VERSION 5.7 ;
  NOWIREEXTENSIONATPIN ON ;
  DIVIDERCHAR "/" ;
  BUSBITCHARS "[]" ;
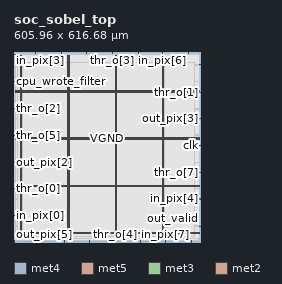
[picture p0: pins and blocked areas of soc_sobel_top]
MACRO soc_sobel_top
  CLASS BLOCK ;
  FOREIGN soc_sobel_top ;
  ORIGIN 0.000 0.000 ;
  SIZE 605.960 BY 616.680 ;
  PIN VGND
    DIRECTION INOUT ;
    USE GROUND ;
    PORT
      LAYER met4 ;
        RECT 24.340 10.640 25.940 604.080 ;
    END
    PORT
      LAYER met4 ;
        RECT 177.940 10.640 179.540 604.080 ;
    END
    PORT
      LAYER met4 ;
        RECT 331.540 10.640 333.140 604.080 ;
    END
    PORT
      LAYER met4 ;
        RECT 485.140 10.640 486.740 604.080 ;
    END
    PORT
      LAYER met5 ;
        RECT 5.280 30.030 600.540 31.630 ;
    END
    PORT
      LAYER met5 ;
        RECT 5.280 183.210 600.540 184.810 ;
    END
    PORT
      LAYER met5 ;
        RECT 5.280 336.390 600.540 337.990 ;
    END
    PORT
      LAYER met5 ;
        RECT 5.280 489.570 600.540 491.170 ;
    END
  END VGND
  PIN VPWR
    DIRECTION INOUT ;
    USE POWER ;
    PORT
      LAYER met4 ;
        RECT 21.040 10.640 22.640 604.080 ;
    END
    PORT
      LAYER met4 ;
        RECT 174.640 10.640 176.240 604.080 ;
    END
    PORT
      LAYER met4 ;
        RECT 328.240 10.640 329.840 604.080 ;
    END
    PORT
      LAYER met4 ;
        RECT 481.840 10.640 483.440 604.080 ;
    END
    PORT
      LAYER met5 ;
        RECT 5.280 26.730 600.540 28.330 ;
    END
    PORT
      LAYER met5 ;
        RECT 5.280 179.910 600.540 181.510 ;
    END
    PORT
      LAYER met5 ;
        RECT 5.280 333.090 600.540 334.690 ;
    END
    PORT
      LAYER met5 ;
        RECT 5.280 486.270 600.540 487.870 ;
    END
  END VPWR
  PIN clk
    DIRECTION INPUT ;
    USE SIGNAL ;
    ANTENNAGATEAREA 0.852000 ;
    PORT
      LAYER met3 ;
        RECT 601.960 312.840 605.960 313.440 ;
    END
  END clk
  PIN cpu_wrote_filter
    DIRECTION OUTPUT TRISTATE ;
    USE SIGNAL ;
    ANTENNADIFFAREA 0.795200 ;
    PORT
      LAYER met3 ;
        RECT 0.000 520.240 4.000 520.840 ;
    END
  END cpu_wrote_filter
  PIN in_pix[0]
    DIRECTION INPUT ;
    USE SIGNAL ;
    ANTENNAGATEAREA 0.247500 ;
    PORT
      LAYER met3 ;
        RECT 0.000 85.040 4.000 85.640 ;
    END
  END in_pix[0]
  PIN in_pix[1]
    DIRECTION INPUT ;
    USE SIGNAL ;
    ANTENNAGATEAREA 0.159000 ;
    PORT
      LAYER met2 ;
        RECT 154.650 612.680 154.930 616.680 ;
    END
  END in_pix[1]
  PIN in_pix[2]
    DIRECTION INPUT ;
    USE SIGNAL ;
    ANTENNAGATEAREA 0.213000 ;
    PORT
      LAYER met2 ;
        RECT 409.030 0.000 409.310 4.000 ;
    END
  END in_pix[2]
  PIN in_pix[3]
    DIRECTION INPUT ;
    USE SIGNAL ;
    ANTENNAGATEAREA 0.213000 ;
    PORT
      LAYER met2 ;
        RECT 70.930 612.680 71.210 616.680 ;
    END
  END in_pix[3]
  PIN in_pix[4]
    DIRECTION INPUT ;
    USE SIGNAL ;
    ANTENNAGATEAREA 0.126000 ;
    PORT
      LAYER met3 ;
        RECT 601.960 139.440 605.960 140.040 ;
    END
  END in_pix[4]
  PIN in_pix[5]
    DIRECTION INPUT ;
    USE SIGNAL ;
    ANTENNAGATEAREA 0.213000 ;
    PORT
      LAYER met2 ;
        RECT 235.150 612.680 235.430 616.680 ;
    END
  END in_pix[5]
  PIN in_pix[6]
    DIRECTION INPUT ;
    USE SIGNAL ;
    ANTENNAGATEAREA 0.213000 ;
    PORT
      LAYER met2 ;
        RECT 483.090 612.680 483.370 616.680 ;
    END
  END in_pix[6]
  PIN in_pix[7]
    DIRECTION INPUT ;
    USE SIGNAL ;
    ANTENNAGATEAREA 0.213000 ;
    PORT
      LAYER met2 ;
        RECT 492.750 0.000 493.030 4.000 ;
    END
  END in_pix[7]
  PIN in_valid
    DIRECTION INPUT ;
    USE SIGNAL ;
    ANTENNAGATEAREA 0.213000 ;
    PORT
      LAYER met3 ;
        RECT 601.960 574.640 605.960 575.240 ;
    END
  END in_valid
  PIN out_pix[0]
    DIRECTION OUTPUT TRISTATE ;
    USE SIGNAL ;
    ANTENNADIFFAREA 0.795200 ;
    PORT
      LAYER met2 ;
        RECT 402.590 612.680 402.870 616.680 ;
    END
  END out_pix[0]
  PIN out_pix[1]
    DIRECTION OUTPUT TRISTATE ;
    USE SIGNAL ;
    ANTENNADIFFAREA 0.795200 ;
    PORT
      LAYER met2 ;
        RECT 566.810 612.680 567.090 616.680 ;
    END
  END out_pix[1]
  PIN out_pix[2]
    DIRECTION OUTPUT TRISTATE ;
    USE SIGNAL ;
    ANTENNADIFFAREA 0.795200 ;
    PORT
      LAYER met3 ;
        RECT 0.000 258.440 4.000 259.040 ;
    END
  END out_pix[2]
  PIN out_pix[3]
    DIRECTION OUTPUT TRISTATE ;
    USE SIGNAL ;
    ANTENNADIFFAREA 0.445500 ;
    PORT
      LAYER met3 ;
        RECT 601.960 401.240 605.960 401.840 ;
    END
  END out_pix[3]
  PIN out_pix[4]
    DIRECTION OUTPUT TRISTATE ;
    USE SIGNAL ;
    ANTENNADIFFAREA 0.795200 ;
    PORT
      LAYER met2 ;
        RECT 576.470 0.000 576.750 4.000 ;
    END
  END out_pix[4]
  PIN out_pix[5]
    DIRECTION OUTPUT TRISTATE ;
    USE SIGNAL ;
    ANTENNADIFFAREA 0.795200 ;
    PORT
      LAYER met2 ;
        RECT 0.090 0.000 0.370 4.000 ;
    END
  END out_pix[5]
  PIN out_pix[6]
    DIRECTION OUTPUT TRISTATE ;
    USE SIGNAL ;
    ANTENNADIFFAREA 0.795200 ;
    PORT
      LAYER met2 ;
        RECT 80.590 0.000 80.870 4.000 ;
    END
  END out_pix[6]
  PIN out_pix[7]
    DIRECTION OUTPUT TRISTATE ;
    USE SIGNAL ;
    ANTENNADIFFAREA 0.795200 ;
    PORT
      LAYER met2 ;
        RECT 164.310 0.000 164.590 4.000 ;
    END
  END out_pix[7]
  PIN out_valid
    DIRECTION OUTPUT TRISTATE ;
    USE SIGNAL ;
    ANTENNADIFFAREA 0.445500 ;
    PORT
      LAYER met3 ;
        RECT 601.960 51.040 605.960 51.640 ;
    END
  END out_valid
  PIN resetn
    DIRECTION INPUT ;
    USE SIGNAL ;
    ANTENNAGATEAREA 0.426000 ;
    PORT
      LAYER met2 ;
        RECT 244.810 0.000 245.090 4.000 ;
    END
  END resetn
  PIN thr_o[0]
    DIRECTION OUTPUT TRISTATE ;
    USE SIGNAL ;
    ANTENNADIFFAREA 0.795200 ;
    PORT
      LAYER met3 ;
        RECT 0.000 173.440 4.000 174.040 ;
    END
  END thr_o[0]
  PIN thr_o[1]
    DIRECTION OUTPUT TRISTATE ;
    USE SIGNAL ;
    ANTENNADIFFAREA 0.445500 ;
    PORT
      LAYER met3 ;
        RECT 601.960 486.240 605.960 486.840 ;
    END
  END thr_o[1]
  PIN thr_o[2]
    DIRECTION OUTPUT TRISTATE ;
    USE SIGNAL ;
    ANTENNADIFFAREA 0.795200 ;
    PORT
      LAYER met3 ;
        RECT 0.000 431.840 4.000 432.440 ;
    END
  END thr_o[2]
  PIN thr_o[3]
    DIRECTION OUTPUT TRISTATE ;
    USE SIGNAL ;
    ANTENNADIFFAREA 0.795200 ;
    PORT
      LAYER met2 ;
        RECT 318.870 612.680 319.150 616.680 ;
    END
  END thr_o[3]
  PIN thr_o[4]
    DIRECTION OUTPUT TRISTATE ;
    USE SIGNAL ;
    ANTENNADIFFAREA 0.795200 ;
    PORT
      LAYER met2 ;
        RECT 328.530 0.000 328.810 4.000 ;
    END
  END thr_o[4]
  PIN thr_o[5]
    DIRECTION OUTPUT TRISTATE ;
    USE SIGNAL ;
    ANTENNADIFFAREA 0.795200 ;
    PORT
      LAYER met3 ;
        RECT 0.000 346.840 4.000 347.440 ;
    END
  END thr_o[5]
  PIN thr_o[6]
    DIRECTION OUTPUT TRISTATE ;
    USE SIGNAL ;
    ANTENNADIFFAREA 0.795200 ;
    PORT
      LAYER met3 ;
        RECT 0.000 608.640 4.000 609.240 ;
    END
  END thr_o[6]
  PIN thr_o[7]
    DIRECTION OUTPUT TRISTATE ;
    USE SIGNAL ;
    ANTENNADIFFAREA 0.445500 ;
    PORT
      LAYER met3 ;
        RECT 601.960 224.440 605.960 225.040 ;
    END
  END thr_o[7]
  OBS
      LAYER li1 ;
        RECT 5.520 10.795 600.300 603.925 ;
      LAYER met1 ;
        RECT 0.070 10.640 600.600 604.080 ;
      LAYER met2 ;
        RECT 0.100 612.400 70.650 612.680 ;
        RECT 71.490 612.400 154.370 612.680 ;
        RECT 155.210 612.400 234.870 612.680 ;
        RECT 235.710 612.400 318.590 612.680 ;
        RECT 319.430 612.400 402.310 612.680 ;
        RECT 403.150 612.400 482.810 612.680 ;
        RECT 483.650 612.400 566.530 612.680 ;
        RECT 567.370 612.400 598.370 612.680 ;
        RECT 0.100 4.280 598.370 612.400 ;
        RECT 0.650 3.670 80.310 4.280 ;
        RECT 81.150 3.670 164.030 4.280 ;
        RECT 164.870 3.670 244.530 4.280 ;
        RECT 245.370 3.670 328.250 4.280 ;
        RECT 329.090 3.670 408.750 4.280 ;
        RECT 409.590 3.670 492.470 4.280 ;
        RECT 493.310 3.670 576.190 4.280 ;
        RECT 577.030 3.670 598.370 4.280 ;
      LAYER met3 ;
        RECT 4.400 608.240 601.960 609.090 ;
        RECT 3.990 575.640 601.960 608.240 ;
        RECT 3.990 574.240 601.560 575.640 ;
        RECT 3.990 521.240 601.960 574.240 ;
        RECT 4.400 519.840 601.960 521.240 ;
        RECT 3.990 487.240 601.960 519.840 ;
        RECT 3.990 485.840 601.560 487.240 ;
        RECT 3.990 432.840 601.960 485.840 ;
        RECT 4.400 431.440 601.960 432.840 ;
        RECT 3.990 402.240 601.960 431.440 ;
        RECT 3.990 400.840 601.560 402.240 ;
        RECT 3.990 347.840 601.960 400.840 ;
        RECT 4.400 346.440 601.960 347.840 ;
        RECT 3.990 313.840 601.960 346.440 ;
        RECT 3.990 312.440 601.560 313.840 ;
        RECT 3.990 259.440 601.960 312.440 ;
        RECT 4.400 258.040 601.960 259.440 ;
        RECT 3.990 225.440 601.960 258.040 ;
        RECT 3.990 224.040 601.560 225.440 ;
        RECT 3.990 174.440 601.960 224.040 ;
        RECT 4.400 173.040 601.960 174.440 ;
        RECT 3.990 140.440 601.960 173.040 ;
        RECT 3.990 139.040 601.560 140.440 ;
        RECT 3.990 86.040 601.960 139.040 ;
        RECT 4.400 84.640 601.960 86.040 ;
        RECT 3.990 52.040 601.960 84.640 ;
        RECT 3.990 50.640 601.560 52.040 ;
        RECT 3.990 10.715 601.960 50.640 ;
      LAYER met4 ;
        RECT 11.335 17.855 20.640 581.225 ;
        RECT 23.040 17.855 23.940 581.225 ;
        RECT 26.340 17.855 174.240 581.225 ;
        RECT 176.640 17.855 177.540 581.225 ;
        RECT 179.940 17.855 327.840 581.225 ;
        RECT 330.240 17.855 331.140 581.225 ;
        RECT 333.540 17.855 481.440 581.225 ;
        RECT 483.840 17.855 484.740 581.225 ;
        RECT 487.140 17.855 586.665 581.225 ;
  END
END soc_sobel_top
END LIBRARY

